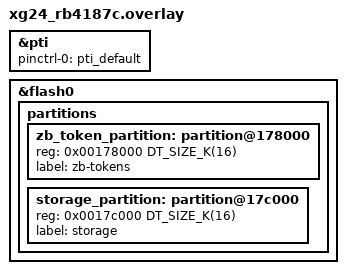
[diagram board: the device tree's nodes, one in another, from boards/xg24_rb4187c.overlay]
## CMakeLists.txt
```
# Copyright (c) 2026 Silicon Laboratories Inc.
# SPDX-License-Identifier: Apache-2.0

cmake_minimum_required(VERSION 3.20.0)

set(CONF_FILE "prj_z3_light_components.conf;prj.conf" CACHE STRING "Zigbee sample configs" FORCE)

find_package(Zephyr REQUIRED HINTS $ENV{ZEPHYR_BASE})
project(zigbee_z3_light)

# SDK/framework sources (hal_silabs) include zap-config.h via af.h; expose
# app autogen globally, not only on the app target.
zephyr_include_directories(${CMAKE_CURRENT_SOURCE_DIR}/autogen)

target_sources(app PRIVATE
  src/main.c
  src/app.c
  autogen/zap-event.c
  autogen/zap-cluster-command-parser.c
  autogen/sl_cluster_service_gen.c
  autogen/zigbee_stack_callback_dispatcher.c
  autogen/zigbee_zcl_callback_dispatcher.c
  autogen/zigbee_common_callback_dispatcher.c
)
```

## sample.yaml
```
sample:
  name: Silicon Labs Zigbee Z3 Light
  description: >
    Zephyr port of the Silicon Labs Zigbee Z3 Light sample. Links the Zigbee PRO
    stack prebuilt libraries and enables the Z3 Light component profile.
tests:
  sample.zigbee.z3_light:
    harness: none
    integration_platforms:
      - xg24_rb4187c
    tags:
      - zigbee
    build_only: true
```

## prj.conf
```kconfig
CONFIG_FLASH=y
CONFIG_FLASH_MAP=y
CONFIG_NVS=y
CONFIG_SETTINGS=y
CONFIG_SETTINGS_NVS=y

CONFIG_GPIO=y

CONFIG_ZIGBEE_SILABS=y
# Z3 Light uses the coordinator/router stack.
CONFIG_ZIGBEE_SILABS_STACK_COORDINATOR=y
CONFIG_ZIGBEE_SILABS_R23_SUPPORT=y
CONFIG_ZIGBEE_SILABS_CBKE=y
CONFIG_ZIGBEE_SILABS_DEBUG_BASIC=y
CONFIG_ZIGBEE_SILABS_SOURCE_ROUTE=y
CONFIG_ZIGBEE_SILABS_GP=y
CONFIG_ZIGBEE_SILABS_ZLL=y

CONFIG_LOG=y
CONFIG_PRINTK=y
CONFIG_REBOOT=y

CONFIG_ENTROPY_GENERATOR=y
CONFIG_SILABS_ZIGBEE_RUNTIME=y
CONFIG_SILABS_ZIGBEE_RUNTIME_THREAD=y
# Match 16 KiB zb_token_partition (2 x 8 KiB pages).
CONFIG_SILABS_ZIGBEE_TOKEN_NVS_SECTOR_COUNT=2

# Zephyr PM owns sleep entry (pm_state_set → SiSDK sl_power_manager_sleep).
# Pulls SILABS_SISDK_POWER_MANAGER / HFXO_MANAGER defaults on S2.
CONFIG_PM=y

# Enable Zephyr PTI driver (silabs,pti DT node in boards/*.overlay).
CONFIG_DEBUG_DRIVER=y
CONFIG_SILABS_SISDK_ZIGBEE_DEBUG_PRINT=y

# Zephyr Shell front-end + SiSDK command dispatch (framework + plugin CLIs).
CONFIG_SHELL=y
CONFIG_SHELL_BACKEND_SERIAL=y
CONFIG_SILABS_SISDK_CLI=y
CONFIG_SILABS_SISDK_ZIGBEE_CLI=y
CONFIG_SILABS_SISDK_ZIGBEE_CORE_CLI=y
CONFIG_SILABS_SISDK_ZIGBEE_ZCL_CLI=y
```

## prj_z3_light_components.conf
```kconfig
# Generated by scripts/gen_zigbee_components.py
# Enable active Zigbee component sources for this application profile.

CONFIG_SILABS_SISDK_ZIGBEE_BYTE_UTILITIES=y
CONFIG_SILABS_SISDK_ZIGBEE_APPLICATION_BOOTLOADER=y
CONFIG_SILABS_SISDK_ZIGBEE_BASIC=y
CONFIG_SILABS_SISDK_ZIGBEE_CLI=y
CONFIG_SILABS_SISDK_ZIGBEE_CLUSTER_SERVICE=y
CONFIG_SILABS_SISDK_ZIGBEE_COLOR_CONTROL_SERVER=y
CONFIG_SILABS_SISDK_ZIGBEE_CORE_CLI=y
CONFIG_SILABS_SISDK_ZIGBEE_COUNTERS=y
CONFIG_SILABS_SISDK_ZIGBEE_DEBUG_BASIC_COMPONENT=y
CONFIG_SILABS_SISDK_ZIGBEE_DEBUG_BASIC_LIBRARY=y
CONFIG_SILABS_SISDK_ZIGBEE_DEBUG_PRINT=y
CONFIG_SILABS_SISDK_ZIGBEE_DEVICE_CONFIG=y
CONFIG_SILABS_SISDK_ZIGBEE_ENHANCED_ROUTING=y
CONFIG_SILABS_SISDK_ZIGBEE_FIND_AND_BIND_TARGET=y
CONFIG_SILABS_SISDK_ZIGBEE_GP=y
CONFIG_SILABS_SISDK_ZIGBEE_GP_LIBRARY=y
CONFIG_SILABS_SISDK_ZIGBEE_GREEN_POWER_CLIENT=y
CONFIG_SILABS_SISDK_ZIGBEE_GREEN_POWER_CLIENT_CLI=y
CONFIG_SILABS_SISDK_ZIGBEE_GREEN_POWER_COMMON=y
CONFIG_SILABS_SISDK_ZIGBEE_GROUPS_SERVER=y
CONFIG_SILABS_SISDK_ZIGBEE_IDENTIFY=y
CONFIG_SILABS_SISDK_ZIGBEE_INTERPAN=y
CONFIG_SILABS_SISDK_ZIGBEE_LEVEL_CONTROL=y
CONFIG_SILABS_SISDK_ZIGBEE_NETWORK_CREATOR=y
CONFIG_SILABS_SISDK_ZIGBEE_NETWORK_CREATOR_SECURITY=y
CONFIG_SILABS_SISDK_ZIGBEE_NETWORK_STEERING=y
CONFIG_SILABS_SISDK_ZIGBEE_ON_OFF=y
CONFIG_SILABS_SISDK_ZIGBEE_PHY_2_4=y
CONFIG_SILABS_SISDK_ZIGBEE_PRO_STACK=y
CONFIG_SILABS_SISDK_ZIGBEE_PRO_STACK_BASIC=y
CONFIG_SILABS_SISDK_ZIGBEE_PRO_STACK_LIBRARY=y
CONFIG_SILABS_SISDK_ZIGBEE_REPORTING=y
CONFIG_SILABS_SISDK_ZIGBEE_SCAN_DISPATCH=y
CONFIG_SILABS_SISDK_ZIGBEE_SCENES=y
CONFIG_SILABS_SISDK_ZIGBEE_SECURE_KEY_STORAGE=y
CONFIG_SILABS_SISDK_ZIGBEE_SECURE_KEY_STORAGE_UPGRADE=y
CONFIG_SILABS_SISDK_ZIGBEE_SECURITY_MANAGER=y
CONFIG_SILABS_SISDK_ZIGBEE_SIGNATURE_DECODE=y
CONFIG_SILABS_SISDK_ZIGBEE_SOURCE_ROUTE_COMPONENT=y
CONFIG_SILABS_SISDK_ZIGBEE_SOURCE_ROUTE_LIBRARY=y
CONFIG_SILABS_SISDK_ZIGBEE_STACK_COMMON=y
CONFIG_SILABS_SISDK_ZIGBEE_STACK_DIAGNOSTICS=y
CONFIG_SILABS_SISDK_ZIGBEE_STRONG_RANDOM_API_PSA=y
CONFIG_SILABS_SISDK_ZIGBEE_SYSTEM_COMMON=y
CONFIG_SILABS_SISDK_ZIGBEE_SYSTEM_COMMON_APP_FRAMEWORK=y
CONFIG_SILABS_SISDK_ZIGBEE_UPDATE_TC_LINK_KEY=y
CONFIG_SILABS_SISDK_ZIGBEE_ZCL_CLI=y
CONFIG_SILABS_SISDK_ZIGBEE_ZCL_FRAMEWORK_CORE=y
CONFIG_SILABS_SISDK_ZIGBEE_ZLL=y
CONFIG_SILABS_SISDK_ZIGBEE_ZLL_COMMISSIONING_COMMON=y
CONFIG_SILABS_SISDK_ZIGBEE_ZLL_COMMISSIONING_SERVER=y
CONFIG_SILABS_SISDK_ZIGBEE_ZLL_IDENTIFY_SERVER=y
CONFIG_SILABS_SISDK_ZIGBEE_ZLL_LEVEL_CONTROL_SERVER=y
CONFIG_SILABS_SISDK_ZIGBEE_ZLL_LIBRARY=y
CONFIG_SILABS_SISDK_ZIGBEE_ZLL_ON_OFF_SERVER=y
CONFIG_SILABS_SISDK_ZIGBEE_ZLL_SCENES_SERVER=y
CONFIG_SILABS_SISDK_ZIGBEE_ZLL_UTILITY_SERVER=y
```

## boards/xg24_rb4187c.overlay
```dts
/*
 * Copyright (c) 2026 Silicon Laboratories Inc.
 * SPDX-License-Identifier: Apache-2.0
 *
 * - Enable Zephyr silabs,pti (debug_silabs_pti.c) instead of SiSDK PTI util.
 * - Split the 32 KiB storage region so Zigbee token NVS and PSA ITS/settings
 *   do not share one NVS mount.
 */

&pti {
	pinctrl-0 = <&pti_default>;
	pinctrl-names = "default";
	status = "okay";
};

&flash0 {
	partitions {
		/*
		 * Replace the board's single 32 KiB storage_partition with two
		 * 16 KiB regions (2 x 8 KiB pages each on Series-2).
		 */
		/delete-node/ partition@178000;

		zb_token_partition: partition@178000 {
			reg = <0x00178000 DT_SIZE_K(16)>;
			label = "zb-tokens";
		};

		storage_partition: partition@17c000 {
			reg = <0x0017c000 DT_SIZE_K(16)>;
			label = "storage";
		};
	};
};
```

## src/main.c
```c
/*
 * Copyright (c) 2026 Silicon Laboratories Inc.
 *
 * SPDX-License-Identifier: Apache-2.0
 */

#include <zephyr/kernel.h>
#include <zephyr/logging/log.h>

#include "sl_status.h"
#include "sl_zigbee_runtime.h"

LOG_MODULE_REGISTER(zigbee_z3_light, LOG_LEVEL_INF);

int main(void)
{
	sl_status_t status;

	LOG_INF("Silicon Labs Zigbee Z3 Light");

	status = sl_zigbee_runtime_init();
	if (status != SL_STATUS_OK) {
		LOG_ERR("Zigbee runtime init failed: 0x%04x", status);
		return 1;
	}

#if defined(CONFIG_SILABS_ZIGBEE_RUNTIME_THREAD)
	status = sl_zigbee_runtime_start();
	if (status != SL_STATUS_OK) {
		LOG_ERR("Zigbee runtime thread start failed: 0x%04x", status);
		return 1;
	}
#endif

	while (true) {
#if !defined(CONFIG_SILABS_ZIGBEE_RUNTIME_THREAD)
		sl_zigbee_runtime_process_once();
		k_msleep(sl_zigbee_runtime_ms_until_next_tick());
#else
		k_sleep(K_FOREVER);
#endif
	}

	return 0;
}
```

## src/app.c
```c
/*
 * Copyright (c) 2026 Silicon Laboratories Inc.
 *
 * SPDX-License-Identifier: Apache-2.0
 *
 * Z3 Light application callbacks (SiSDK app.c), with Zephyr GPIO for LED/button.
 */

#include <zephyr/device.h>
#include <zephyr/drivers/gpio.h>
#include <zephyr/devicetree.h>
#include <zephyr/logging/log.h>

#include "app/framework/include/af.h"
#ifdef SL_COMPONENT_CATALOG_PRESENT
#include "sl_component_catalog.h"
#endif

#include "network-creator.h"
#include "network-creator-security.h"
#include "network-steering.h"
#include "find-and-bind-target.h"

#ifdef SL_CATALOG_ZIGBEE_ZLL_COMMISSIONING_COMMON_PRESENT
#include "zll-commissioning.h"
#endif //SL_CATALOG_ZIGBEE_ZLL_COMMISSIONING_COMMON_PRESENT

LOG_MODULE_REGISTER(zigbee_z3_light_app, CONFIG_LOG_DEFAULT_LEVEL);

#define LED_BLINK_PERIOD_MS     2000
#define LIGHT_ENDPOINT          1
#define ZIGBEE_STARTUP_DELAY_MS 40

#if DT_NODE_HAS_STATUS(DT_ALIAS(led0), okay)
static const struct gpio_dt_spec app_led = GPIO_DT_SPEC_GET(DT_ALIAS(led0), gpios);

static void led_turn_on(void)
{
	(void)gpio_pin_set_dt(&app_led, 1);
}

static void led_turn_off(void)
{
	(void)gpio_pin_set_dt(&app_led, 0);
}

static void led_toggle(void)
{
	(void)gpio_pin_toggle_dt(&app_led);
}
#else
static void led_turn_on(void)
{
}

static void led_turn_off(void)
{
}

static void led_toggle(void)
{
}
#endif

static sl_zigbee_af_event_t commissioning_led_event;
static sl_zigbee_af_event_t finding_and_binding_event;

#if DT_NODE_HAS_STATUS(DT_ALIAS(sw0), okay)
static const struct gpio_dt_spec app_btn = GPIO_DT_SPEC_GET(DT_ALIAS(sw0), gpios);
static struct gpio_callback app_btn_cb;

static void app_btn_isr(const struct device *dev, struct gpio_callback *cb, uint32_t pins)
{
	ARG_UNUSED(dev);
	ARG_UNUSED(cb);
	ARG_UNUSED(pins);

	/* Released (inactive) → start find-and-bind, same as SiSDK button path. */
	sl_zigbee_af_event_set_active(&finding_and_binding_event);
}
#endif

static void app_gpio_init(void)
{
#if DT_NODE_HAS_STATUS(DT_ALIAS(led0), okay)
	if (!gpio_is_ready_dt(&app_led)) {
		LOG_ERR("LED GPIO device not ready");
	} else if (gpio_pin_configure_dt(&app_led, GPIO_OUTPUT_INACTIVE) != 0) {
		LOG_ERR("failed to configure LED GPIO");
	}
#endif

#if DT_NODE_HAS_STATUS(DT_ALIAS(sw0), okay)
	if (!gpio_is_ready_dt(&app_btn)) {
		LOG_ERR("button GPIO device not ready");
		return;
	}

	if (gpio_pin_configure_dt(&app_btn, GPIO_INPUT) != 0) {
		LOG_ERR("failed to configure button GPIO");
		return;
	}

	if (gpio_pin_interrupt_configure_dt(&app_btn, GPIO_INT_EDGE_TO_INACTIVE) != 0) {
		LOG_ERR("failed to configure button interrupt");
		return;
	}

	gpio_init_callback(&app_btn_cb, app_btn_isr, BIT(app_btn.pin));
	gpio_add_callback(app_btn.port, &app_btn_cb);
#endif
}

static void commissioning_led_event_handler(sl_zigbee_af_event_t *event)
{
	(void)event;

	if (sl_zigbee_af_network_state() == SL_ZIGBEE_JOINED_NETWORK) {
		uint16_t identifyTime;

		sl_zigbee_af_read_server_attribute(LIGHT_ENDPOINT,
						   ZCL_IDENTIFY_CLUSTER_ID,
						   ZCL_IDENTIFY_TIME_ATTRIBUTE_ID,
						   (uint8_t *)&identifyTime,
						   sizeof(identifyTime));
		if (identifyTime > 0) {
			led_toggle();
			sl_zigbee_af_event_set_delay_ms(&commissioning_led_event,
							LED_BLINK_PERIOD_MS << 1);
		} else {
			led_turn_on();
		}
	} else {
		sl_zigbee_af_network_steering_autostart();
	}
}

static void finding_and_binding_event_handler(sl_zigbee_af_event_t *event)
{
	(void)event;

	if (sl_zigbee_af_network_state() == SL_ZIGBEE_JOINED_NETWORK) {
		sl_zigbee_af_event_set_inactive(&finding_and_binding_event);
		sl_zigbee_app_debug_println("Find and bind target start: 0x%02X",
					   sl_zigbee_af_find_and_bind_target_start(LIGHT_ENDPOINT));
	}
}

//----------------------
// Implemented Callbacks

/** @brief Stack Status
 *
 * This function is called by the application framework from the stack status
 * handler.  This callbacks provides applications an opportunity to be notified
 * of changes to the stack status and take appropriate action. The framework
 * will always process the stack status after the callback returns.
 */
void sl_zigbee_af_stack_status_cb(sl_status_t status)
{
	if (status == SL_STATUS_NETWORK_DOWN) {
		led_turn_off();
	} else if (status == SL_STATUS_NETWORK_UP) {
		led_turn_on();
		sl_zigbee_af_event_set_active(&finding_and_binding_event);
	}
}

/** @brief Init
 * Application init function
 */
void sl_zigbee_af_main_init_cb(void)
{
	app_gpio_init();

	sl_zigbee_af_event_init(&commissioning_led_event, commissioning_led_event_handler);
	sl_zigbee_af_isr_event_init(&finding_and_binding_event, finding_and_binding_event_handler);

  // Start the commissioning LED event after network is up, and communicated to app framework task in the main loop
  sl_zigbee_af_event_set_delay_ms(&commissioning_led_event, ZIGBEE_STARTUP_DELAY_MS);
}

/** @brief Complete network steering.
 *
 * This callback is fired when the Network Steering plugin is complete.
 *
 * @param status On success this will be set to SL_STATUS_OK to indicate a
 * network was joined successfully. On failure this will be the status code of
 * the last join or scan attempt.
 *
 * @param totalBeacons The total number of 802.15.4 beacons that were heard,
 * including beacons from different devices with the same PAN ID.
 *
 * @param joinAttempts The number of join attempts that were made to get onto
 * an open Zigbee network.
 *
 * @param finalState The finishing state of the network steering process. From
 * this, one is able to tell on which channel mask and with which key the
 * process was complete.
 */
void sl_zigbee_af_network_steering_complete_cb(sl_status_t status,
                                               uint8_t totalBeacons,
                                               uint8_t joinAttempts,
                                               uint8_t finalState)
{
	(void)totalBeacons;
	(void)joinAttempts;
	(void)finalState;

	sl_zigbee_app_debug_println("Join network complete: 0x%02X", status);

	if (status != SL_STATUS_OK) {
#ifdef SL_CATALOG_ZIGBEE_ZLL_COMMISSIONING_COMMON_PRESENT
		status = sl_zigbee_af_zll_set_initial_security_state();
		if (status != SL_STATUS_OK) {
			sl_zigbee_app_debug_println("Error: cannot initialize ZLL security: 0x%02X",
						    status);
		}
#endif
		status = sl_zigbee_af_network_creator_start(false); /* distributed */
		sl_zigbee_app_debug_println("Form network start: 0x%02X", status);
	}
}

/** @brief Complete the network creation process.
 *
 * This callback notifies the user that the network creation process has
 * completed successfully.
 *
 * @param network The network that the network creator plugin successfully
 * formed.
 *
 * @param usedSecondaryChannels Whether or not the network creator wants to
 * form a network on the secondary channels.
 */
void sl_zigbee_af_network_creator_complete_cb(const sl_zigbee_network_parameters_t *network,
					      bool usedSecondaryChannels)
{
	(void)network;
	(void)usedSecondaryChannels;

	sl_zigbee_app_debug_println("Form Network Complete: 0x%02X", SL_STATUS_OK);
}

/** @brief Post Attribute Change
 *
 * This function is called by the application framework after it changes an
 * attribute value. The value passed into this callback is the value to which
 * the attribute was set by the framework.
 */
void sl_zigbee_af_post_attribute_change_cb(uint8_t endpoint,
                                           sl_zigbee_af_cluster_id_t clusterId,
                                           sl_zigbee_af_attribute_id_t attributeId,
                                           uint8_t mask,
                                           uint16_t manufacturerCode,
                                           uint8_t type,
                                           uint8_t size,
                                           uint8_t* value)
{
	(void)manufacturerCode;
	(void)type;
	(void)size;
	(void)value;

	if (clusterId == ZCL_ON_OFF_CLUSTER_ID && attributeId == ZCL_ON_OFF_ATTRIBUTE_ID &&
	    mask == CLUSTER_MASK_SERVER) {
		bool onOff;

		if (sl_zigbee_af_read_server_attribute(endpoint, ZCL_ON_OFF_CLUSTER_ID,
						       ZCL_ON_OFF_ATTRIBUTE_ID, (uint8_t *)&onOff,
						       sizeof(onOff)) ==
		    SL_ZIGBEE_ZCL_STATUS_SUCCESS) {
			if (onOff) {
				led_turn_on();
			} else {
				led_turn_off();
			}
		}
	}
}

/** @brief On/off Cluster Server Post Init
 *
 * Following resolution of the On/Off state at startup for this endpoint, perform any
 * additional initialization needed; e.g., synchronize hardware state.
 *
 * @param endpoint Endpoint that is being initialized
 */
void sl_zigbee_af_on_off_cluster_server_post_init_cb(uint8_t endpoint)
{
  // At startup, trigger a read of the attribute and possibly a toggle of the
  // LED to make sure they are always in sync.
  sl_zigbee_af_post_attribute_change_cb(endpoint,
                                        ZCL_ON_OFF_CLUSTER_ID,
                                        ZCL_ON_OFF_ATTRIBUTE_ID,
                                        CLUSTER_MASK_SERVER,
                                        0,
                                        0,
                                        0,
                                        NULL);
}

/** @brief
 *
 * Application framework equivalent of ::sl_zigbee_radio_needs_calibrating_handler
 */
void sl_zigbee_af_radio_needs_calibrating_cb(void)
{
#ifndef EZSP_HOST
	sl_mac_calibrate_current_channel();
#endif
}
```

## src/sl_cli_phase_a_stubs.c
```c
/*
 * Temporary weak stubs for Studio command-table handlers compiled out
 * behind unavailable catalog symbols (rail phy select).
 */

#include "sl_cli_types.h"

__attribute__((weak)) void sli_get_pti_radio_config(sl_cli_command_arg_t *arguments)
{
	(void)arguments;
}

__attribute__((weak)) void sli_zigbee_cli_get_active_phy_command(sl_cli_command_arg_t *arguments)
{
	(void)arguments;
}
```

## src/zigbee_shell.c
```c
/*
 * Copyright (c) 2026 Silicon Laboratories Inc.
 *
 * SPDX-License-Identifier: Apache-2.0
 *
 * Zephyr Shell bridge: forward "zigbee <sl-cli-line>" to sl_cli_command_execute().
 */

#include <stdio.h>
#include <string.h>

#include <zephyr/kernel.h>
#include <zephyr/shell/shell.h>

#include "sl_cli.h"
#include "sl_cli_command.h"
#include "sl_cli_config.h"
#include "sl_cli_io_zephyr.h"
#include "sl_status.h"

#ifndef ZIGBEE_SHELL_LINE_MAX
#define ZIGBEE_SHELL_LINE_MAX SL_CLI_INPUT_BUFFER_SIZE
#endif

static int cmd_zigbee(const struct shell *sh, size_t argc, char **argv)
{
	char line[ZIGBEE_SHELL_LINE_MAX];
	size_t pos = 0U;
	sl_status_t status;

	if (argc < 2U) {
		shell_print(sh, "usage: zigbee <sl-cli-command> [args...]");
		return -EINVAL;
	}

	if (sl_cli_default_handle == NULL) {
		shell_error(sh, "Zigbee CLI not initialized");
		return -ENODEV;
	}

	line[0] = '\0';
	for (size_t i = 1U; i < argc; i++) {
		int n;

		if (i > 1U) {
			if (pos + 1U >= sizeof(line)) {
				shell_error(sh, "command too long");
				return -EINVAL;
			}
			line[pos++] = ' ';
			line[pos] = '\0';
		}

		n = snprintf(&line[pos], sizeof(line) - pos, "%s", argv[i]);
		if (n < 0 || (size_t)n >= (sizeof(line) - pos)) {
			shell_error(sh, "command too long");
			return -EINVAL;
		}
		pos += (size_t)n;
	}

	sl_cli_io_zephyr_set_shell(sh);
	status = sl_cli_command_execute(sl_cli_default_handle, line);
	sl_cli_io_zephyr_set_shell(NULL);

	if (status == SL_STATUS_OK) {
		return 0;
	}
	if (status == SL_STATUS_NOT_FOUND) {
		shell_error(sh, "unknown command");
		return -ENOENT;
	}

	shell_error(sh, "command failed: 0x%04x", status);
	return -EIO;
}

SHELL_CMD_ARG_REGISTER(zigbee, NULL, "Zigbee SL CLI (info, network, zcl, ...)",
		       cmd_zigbee, 2, 32);
```
